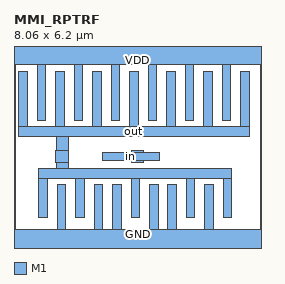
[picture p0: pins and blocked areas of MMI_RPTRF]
MACRO MMI_RPTRF
	CLASS CORE ;
	FOREIGN MMI_RPTRF 0 0 ;
	SIZE 8.06 BY 6.2 ;
	SYMMETRY X Y ;
	SITE CORE1 ;
	PIN out
		DIRECTION output ;
		USE SIGNAL ;
		PORT
			LAYER M1 ;
			RECT 0.15 3.765 0.435 5.575 ;
			LAYER M1 ;
			RECT 1.36 3.765 1.64 5.575 ;
			LAYER M1 ;
			RECT 2.565 3.765 2.85 5.575 ;
			LAYER M1 ;
			RECT 3.77 3.765 4.055 5.575 ;
			LAYER M1 ;
			RECT 4.98 3.765 5.265 5.575 ;
			LAYER M1 ;
			RECT 6.185 3.765 6.47 5.575 ;
			LAYER M1 ;
			RECT 7.39 3.765 7.675 5.575 ;
			LAYER M1 ;
			RECT 0.15 3.43 7.675 3.765 ;
			LAYER M1 ;
			RECT 1.39 2.98 1.77 3.43 ;
			LAYER M1 ;
			RECT 1.36 2.6 1.77 2.98 ;
			LAYER M1 ;
			RECT 1.39 2.395 1.77 2.6 ;
			LAYER M1 ;
			RECT 0.8 2.075 7.11 2.395 ;
			LAYER M1 ;
			RECT 0.8 0.785 1.085 2.075 ;
			LAYER M1 ;
			RECT 2.01 0.785 2.295 2.075 ;
			LAYER M1 ;
			RECT 3.82 0.785 4.105 2.075 ;
			LAYER M1 ;
			RECT 5.62 0.785 5.905 2.075 ;
			LAYER M1 ;
			RECT 6.825 0.785 7.11 2.075 ;
		END
		AntennaDiffArea 9.6763 ;
	END out
	PIN GND
		DIRECTION inout ;
		USE GROUND ;
		PORT
			LAYER M1 ;
			RECT 1.41 0.42 1.695 1.875 ;
			LAYER M1 ;
			RECT 2.615 0.42 2.9 1.875 ;
			LAYER M1 ;
			RECT 3.215 0.42 3.5 1.875 ;
			LAYER M1 ;
			RECT 4.425 0.42 4.71 1.875 ;
			LAYER M1 ;
			RECT 5.015 0.42 5.3 1.875 ;
			LAYER M1 ;
			RECT 6.22 0.42 6.505 1.875 ;
			LAYER M1 ;
			RECT 0 -0.42 8.06 0.42 ;
		END
	END GND
	PIN VDD
		DIRECTION inout ;
		USE POWER ;
		PORT
			LAYER M1 ;
			RECT 0 5.78 8.06 6.62 ;
			LAYER M1 ;
			RECT 0.755 3.97 1.04 5.78 ;
			LAYER M1 ;
			RECT 1.96 3.97 2.245 5.78 ;
			LAYER M1 ;
			RECT 3.17 3.97 3.455 5.78 ;
			LAYER M1 ;
			RECT 4.375 3.97 4.66 5.78 ;
			LAYER M1 ;
			RECT 5.58 3.97 5.865 5.78 ;
			LAYER M1 ;
			RECT 6.79 3.97 7.075 5.78 ;
		END
	END VDD
	PIN in
		DIRECTION input ;
		USE SIGNAL ;
		PORT
			LAYER M1 ;
			RECT 3.84 2.93 4.22 2.98 ;
			LAYER M1 ;
			RECT 2.895 2.65 4.735 2.93 ;
			LAYER M1 ;
			RECT 3.84 2.6 4.22 2.65 ;
		END
		AntennaGateArea 5.556 ;
	END in
	OBS
	END
END MMI_RPTRF
